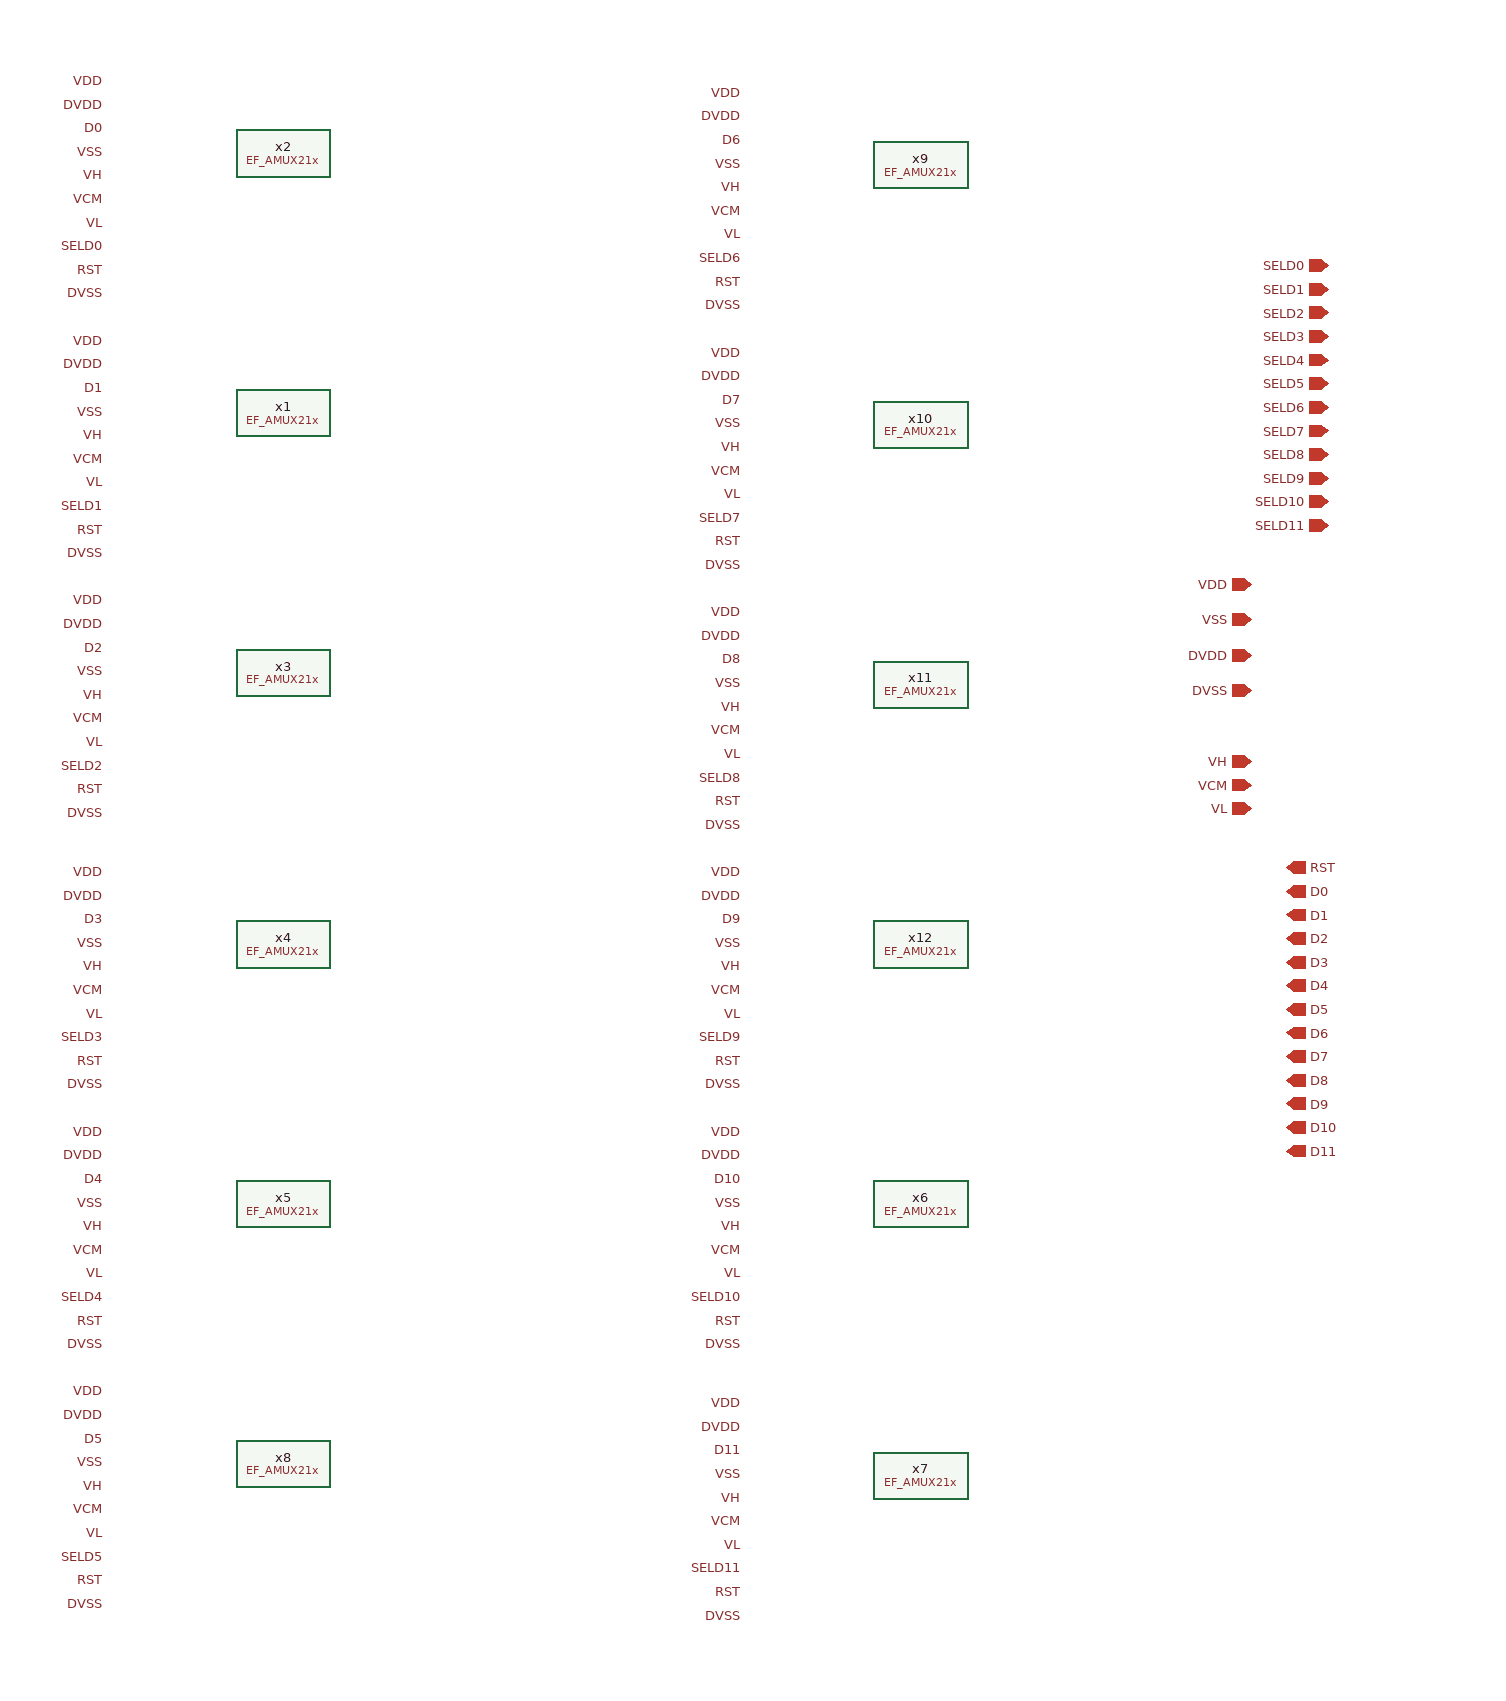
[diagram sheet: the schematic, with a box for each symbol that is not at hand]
v {xschem version=3.4.5 file_version=1.2
}
G {}
K {}
V {}
S {}
E {}
C {devices/lab_pin.sym} 1120 -1085 0 0 {name=p6 sig_type=std_logic lab=VDD}
C {devices/lab_pin.sym} 1120 -1065 0 0 {name=p8 sig_type=std_logic lab=DVDD}
C {EF_AMUX21x.sym} 1270 -1025 0 0 {name=x2}
C {devices/lab_pin.sym} 1120 -1045 0 0 {name=p17 sig_type=std_logic lab=D0}
C {devices/lab_pin.sym} 1120 -1005 0 0 {name=p23 sig_type=std_logic lab=VH}
C {devices/lab_pin.sym} 1120 -945 0 0 {name=p11 sig_type=std_logic lab=SELD0}
C {devices/lab_pin.sym} 1120 -905 0 0 {name=p19 sig_type=std_logic lab=DVSS}
C {devices/lab_pin.sym} 1120 -965 0 0 {name=p22 sig_type=std_logic lab=VL}
C {devices/iopin.sym} 2090 -660 0 0 {name=p32 lab=VDD}
C {devices/iopin.sym} 2090 -600 0 0 {name=p33 lab=DVDD}
C {devices/iopin.sym} 2090 -570 0 0 {name=p34 lab=DVSS}
C {devices/iopin.sym} 2090 -510 0 0 {name=p36 lab=VH}
C {devices/lab_pin.sym} 1120 -865 0 0 {name=p12 sig_type=std_logic lab=VDD}
C {devices/lab_pin.sym} 1120 -845 0 0 {name=p13 sig_type=std_logic lab=DVDD}
C {EF_AMUX21x.sym} 1270 -805 0 0 {name=x1}
C {devices/lab_pin.sym} 1120 -825 0 0 {name=p14 sig_type=std_logic lab=D1}
C {devices/lab_pin.sym} 1120 -725 0 0 {name=p18 sig_type=std_logic lab=SELD1}
C {devices/lab_pin.sym} 1120 -685 0 0 {name=p20 sig_type=std_logic lab=DVSS}
C {devices/iopin.sym} 2090 -470 0 0 {name=p4 lab=VL}
C {devices/lab_pin.sym} 1120 -645 0 0 {name=p21 sig_type=std_logic lab=VDD}
C {devices/lab_pin.sym} 1120 -625 0 0 {name=p24 sig_type=std_logic lab=DVDD}
C {EF_AMUX21x.sym} 1270 -585 0 0 {name=x3}
C {devices/lab_pin.sym} 1120 -605 0 0 {name=p25 sig_type=std_logic lab=D2}
C {devices/lab_pin.sym} 1120 -505 0 0 {name=p28 sig_type=std_logic lab=SELD2}
C {devices/lab_pin.sym} 1120 -465 0 0 {name=p29 sig_type=std_logic lab=DVSS}
C {devices/lab_pin.sym} 1120 -415 0 0 {name=p7 sig_type=std_logic lab=VDD}
C {devices/lab_pin.sym} 1120 -395 0 0 {name=p10 sig_type=std_logic lab=DVDD}
C {EF_AMUX21x.sym} 1270 -355 0 0 {name=x4}
C {devices/lab_pin.sym} 1120 -375 0 0 {name=p30 sig_type=std_logic lab=D3}
C {devices/lab_pin.sym} 1120 -275 0 0 {name=p31 sig_type=std_logic lab=SELD3}
C {devices/lab_pin.sym} 1120 -235 0 0 {name=p35 sig_type=std_logic lab=DVSS}
C {devices/lab_pin.sym} 1120 -195 0 0 {name=p44 sig_type=std_logic lab=VDD}
C {devices/lab_pin.sym} 1120 -175 0 0 {name=p45 sig_type=std_logic lab=DVDD}
C {EF_AMUX21x.sym} 1270 -135 0 0 {name=x5}
C {devices/lab_pin.sym} 1120 -155 0 0 {name=p46 sig_type=std_logic lab=D4}
C {devices/lab_pin.sym} 1120 -55 0 0 {name=p47 sig_type=std_logic lab=SELD4}
C {devices/lab_pin.sym} 1120 -15 0 0 {name=p48 sig_type=std_logic lab=DVSS}
C {devices/lab_pin.sym} 1120 25 0 0 {name=p74 sig_type=std_logic lab=VDD}
C {devices/lab_pin.sym} 1120 45 0 0 {name=p75 sig_type=std_logic lab=DVDD}
C {EF_AMUX21x.sym} 1270 85 0 0 {name=x8}
C {devices/lab_pin.sym} 1120 65 0 0 {name=p76 sig_type=std_logic lab=D5}
C {devices/lab_pin.sym} 1120 165 0 0 {name=p77 sig_type=std_logic lab=SELD5}
C {devices/lab_pin.sym} 1120 205 0 0 {name=p78 sig_type=std_logic lab=DVSS}
C {devices/lab_pin.sym} 1660 -1075 0 0 {name=p86 sig_type=std_logic lab=VDD}
C {devices/lab_pin.sym} 1660 -1055 0 0 {name=p87 sig_type=std_logic lab=DVDD}
C {EF_AMUX21x.sym} 1810 -1015 0 0 {name=x9}
C {devices/lab_pin.sym} 1660 -1035 0 0 {name=p88 sig_type=std_logic lab=D6}
C {devices/lab_pin.sym} 1660 -935 0 0 {name=p89 sig_type=std_logic lab=SELD6}
C {devices/lab_pin.sym} 1660 -895 0 0 {name=p90 sig_type=std_logic lab=DVSS}
C {devices/lab_pin.sym} 1660 -855 0 0 {name=p96 sig_type=std_logic lab=VDD}
C {devices/lab_pin.sym} 1660 -835 0 0 {name=p97 sig_type=std_logic lab=DVDD}
C {EF_AMUX21x.sym} 1810 -795 0 0 {name=x10}
C {devices/lab_pin.sym} 1660 -815 0 0 {name=p98 sig_type=std_logic lab=D7}
C {devices/lab_pin.sym} 1660 -715 0 0 {name=p99 sig_type=std_logic lab=SELD7}
C {devices/lab_pin.sym} 1660 -675 0 0 {name=p100 sig_type=std_logic lab=DVSS}
C {devices/lab_pin.sym} 1660 -635 0 0 {name=p106 sig_type=std_logic lab=VDD}
C {devices/lab_pin.sym} 1660 -615 0 0 {name=p107 sig_type=std_logic lab=DVDD}
C {EF_AMUX21x.sym} 1810 -575 0 0 {name=x11}
C {devices/lab_pin.sym} 1660 -595 0 0 {name=p108 sig_type=std_logic lab=D8}
C {devices/lab_pin.sym} 1660 -495 0 0 {name=p109 sig_type=std_logic lab=SELD8}
C {devices/lab_pin.sym} 1660 -455 0 0 {name=p110 sig_type=std_logic lab=DVSS}
C {devices/lab_pin.sym} 1660 -415 0 0 {name=p116 sig_type=std_logic lab=VDD}
C {devices/lab_pin.sym} 1660 -395 0 0 {name=p117 sig_type=std_logic lab=DVDD}
C {EF_AMUX21x.sym} 1810 -355 0 0 {name=x12}
C {devices/lab_pin.sym} 1660 -375 0 0 {name=p118 sig_type=std_logic lab=D9}
C {devices/lab_pin.sym} 1660 -275 0 0 {name=p119 sig_type=std_logic lab=SELD9}
C {devices/lab_pin.sym} 1660 -235 0 0 {name=p120 sig_type=std_logic lab=DVSS}
C {devices/ipin.sym} 2155 -930 0 0 {name=p61 lab=SELD0}
C {devices/ipin.sym} 2155 -910 0 0 {name=p62 lab=SELD1}
C {devices/ipin.sym} 2155 -890 0 0 {name=p63 lab=SELD2}
C {devices/ipin.sym} 2155 -870 0 0 {name=p64 lab=SELD3}
C {devices/ipin.sym} 2155 -850 0 0 {name=p65 lab=SELD4}
C {devices/ipin.sym} 2155 -830 0 0 {name=p66 lab=SELD5}
C {devices/ipin.sym} 2155 -810 0 0 {name=p67 lab=SELD6}
C {devices/ipin.sym} 2155 -790 0 0 {name=p68 lab=SELD7}
C {devices/ipin.sym} 2155 -770 0 0 {name=p69 lab=SELD8}
C {devices/ipin.sym} 2155 -750 0 0 {name=p70 lab=SELD9}
C {devices/iopin.sym} 2090 -630 0 0 {name=p71 lab=VSS}
C {devices/lab_pin.sym} 1120 -1025 0 0 {name=p72 sig_type=std_logic lab=VSS}
C {devices/lab_pin.sym} 1120 -805 0 0 {name=p73 sig_type=std_logic lab=VSS}
C {devices/lab_pin.sym} 1120 -355 0 0 {name=p80 sig_type=std_logic lab=VSS}
C {devices/lab_pin.sym} 1120 -135 0 0 {name=p81 sig_type=std_logic lab=VSS}
C {devices/lab_pin.sym} 1120 85 0 0 {name=p82 sig_type=std_logic lab=VSS}
C {devices/lab_pin.sym} 1660 -1015 0 0 {name=p83 sig_type=std_logic lab=VSS}
C {devices/lab_pin.sym} 1660 -795 0 0 {name=p84 sig_type=std_logic lab=VSS}
C {devices/lab_pin.sym} 1660 -575 0 0 {name=p85 sig_type=std_logic lab=VSS}
C {devices/lab_pin.sym} 1660 -355 0 0 {name=p91 sig_type=std_logic lab=VSS}
C {devices/iopin.sym} 2120 -400 0 1 {name=p92 lab=D0}
C {devices/iopin.sym} 2120 -380 0 1 {name=p93 lab=D1}
C {devices/iopin.sym} 2120 -360 0 1 {name=p94 lab=D2}
C {devices/iopin.sym} 2120 -340 0 1 {name=p95 lab=D3}
C {devices/iopin.sym} 2120 -320 0 1 {name=p101 lab=D4}
C {devices/iopin.sym} 2120 -300 0 1 {name=p102 lab=D5}
C {devices/iopin.sym} 2120 -280 0 1 {name=p103 lab=D6}
C {devices/iopin.sym} 2120 -260 0 1 {name=p104 lab=D7}
C {devices/iopin.sym} 2120 -240 0 1 {name=p105 lab=D8}
C {devices/iopin.sym} 2120 -220 0 1 {name=p111 lab=D9}
C {devices/ipin.sym} 2155 -730 0 0 {name=p1 lab=SELD10}
C {devices/ipin.sym} 2155 -710 0 0 {name=p2 lab=SELD11}
C {devices/iopin.sym} 2120 -200 0 1 {name=p3 lab=D10}
C {devices/iopin.sym} 2120 -180 0 1 {name=p16 lab=D11}
C {devices/lab_pin.sym} 1660 -195 0 0 {name=p27 sig_type=std_logic lab=VDD}
C {devices/lab_pin.sym} 1660 -175 0 0 {name=p37 sig_type=std_logic lab=DVDD}
C {EF_AMUX21x.sym} 1810 -135 0 0 {name=x6}
C {devices/lab_pin.sym} 1660 -155 0 0 {name=p40 sig_type=std_logic lab=D10}
C {devices/lab_pin.sym} 1660 -55 0 0 {name=p41 sig_type=std_logic lab=SELD10}
C {devices/lab_pin.sym} 1660 -15 0 0 {name=p42 sig_type=std_logic lab=DVSS}
C {devices/lab_pin.sym} 1660 -135 0 0 {name=p113 sig_type=std_logic lab=VSS}
C {devices/lab_pin.sym} 1660 35 0 0 {name=p114 sig_type=std_logic lab=VDD}
C {devices/lab_pin.sym} 1660 55 0 0 {name=p115 sig_type=std_logic lab=DVDD}
C {EF_AMUX21x.sym} 1810 95 0 0 {name=x7}
C {devices/lab_pin.sym} 1660 75 0 0 {name=p121 sig_type=std_logic lab=D11}
C {devices/lab_pin.sym} 1660 175 0 0 {name=p122 sig_type=std_logic lab=SELD11}
C {devices/lab_pin.sym} 1660 215 0 0 {name=p123 sig_type=std_logic lab=DVSS}
C {devices/lab_pin.sym} 1660 95 0 0 {name=p126 sig_type=std_logic lab=VSS}
C {devices/iopin.sym} 2090 -490 0 0 {name=p127 lab=VCM}
C {devices/iopin.sym} 2120 -420 0 1 {name=p128 lab=RST}
C {devices/lab_pin.sym} 1120 -985 0 0 {name=p129 sig_type=std_logic lab=VCM}
C {devices/lab_pin.sym} 1120 -765 0 0 {name=p130 sig_type=std_logic lab=VCM}
C {devices/lab_pin.sym} 1120 -545 0 0 {name=p131 sig_type=std_logic lab=VCM}
C {devices/lab_pin.sym} 1120 -315 0 0 {name=p132 sig_type=std_logic lab=VCM}
C {devices/lab_pin.sym} 1120 -95 0 0 {name=p133 sig_type=std_logic lab=VCM}
C {devices/lab_pin.sym} 1120 125 0 0 {name=p134 sig_type=std_logic lab=VCM}
C {devices/lab_pin.sym} 1660 135 0 0 {name=p135 sig_type=std_logic lab=VCM}
C {devices/lab_pin.sym} 1660 -95 0 0 {name=p136 sig_type=std_logic lab=VCM}
C {devices/lab_pin.sym} 1660 -315 0 0 {name=p137 sig_type=std_logic lab=VCM}
C {devices/lab_pin.sym} 1660 -535 0 0 {name=p138 sig_type=std_logic lab=VCM}
C {devices/lab_pin.sym} 1660 -755 0 0 {name=p139 sig_type=std_logic lab=VCM}
C {devices/lab_pin.sym} 1660 -975 0 0 {name=p140 sig_type=std_logic lab=VCM}
C {devices/lab_pin.sym} 1120 -925 0 0 {name=p141 sig_type=std_logic lab=RST}
C {devices/lab_pin.sym} 1120 -705 0 0 {name=p142 sig_type=std_logic lab=RST}
C {devices/lab_pin.sym} 1120 -485 0 0 {name=p143 sig_type=std_logic lab=RST}
C {devices/lab_pin.sym} 1120 -255 0 0 {name=p144 sig_type=std_logic lab=RST}
C {devices/lab_pin.sym} 1120 -35 0 0 {name=p145 sig_type=std_logic lab=RST}
C {devices/lab_pin.sym} 1120 185 0 0 {name=p146 sig_type=std_logic lab=RST}
C {devices/lab_pin.sym} 1660 195 0 0 {name=p147 sig_type=std_logic lab=RST}
C {devices/lab_pin.sym} 1660 -35 0 0 {name=p148 sig_type=std_logic lab=RST}
C {devices/lab_pin.sym} 1660 -255 0 0 {name=p149 sig_type=std_logic lab=RST}
C {devices/lab_pin.sym} 1660 -475 0 0 {name=p150 sig_type=std_logic lab=RST}
C {devices/lab_pin.sym} 1660 -695 0 0 {name=p151 sig_type=std_logic lab=RST}
C {devices/lab_pin.sym} 1660 -915 0 0 {name=p152 sig_type=std_logic lab=RST}
C {devices/lab_pin.sym} 1120 -745 0 0 {name=p15 sig_type=std_logic lab=VL}
C {devices/lab_pin.sym} 1120 -525 0 0 {name=p43 sig_type=std_logic lab=VL}
C {devices/lab_pin.sym} 1120 -585 0 0 {name=p5 sig_type=std_logic lab=VSS}
C {devices/lab_pin.sym} 1120 -295 0 0 {name=p38 sig_type=std_logic lab=VL}
C {devices/lab_pin.sym} 1120 -75 0 0 {name=p50 sig_type=std_logic lab=VL}
C {devices/lab_pin.sym} 1120 145 0 0 {name=p52 sig_type=std_logic lab=VL}
C {devices/lab_pin.sym} 1660 155 0 0 {name=p54 sig_type=std_logic lab=VL}
C {devices/lab_pin.sym} 1660 -75 0 0 {name=p56 sig_type=std_logic lab=VL}
C {devices/lab_pin.sym} 1660 -295 0 0 {name=p58 sig_type=std_logic lab=VL}
C {devices/lab_pin.sym} 1660 -515 0 0 {name=p60 sig_type=std_logic lab=VL}
C {devices/lab_pin.sym} 1660 -735 0 0 {name=p112 sig_type=std_logic lab=VL}
C {devices/lab_pin.sym} 1660 -955 0 0 {name=p125 sig_type=std_logic lab=VL}
C {devices/lab_pin.sym} 1120 -785 0 0 {name=p9 sig_type=std_logic lab=VH}
C {devices/lab_pin.sym} 1120 -335 0 0 {name=p26 sig_type=std_logic lab=VH}
C {devices/lab_pin.sym} 1120 -565 0 0 {name=p39 sig_type=std_logic lab=VH}
C {devices/lab_pin.sym} 1120 -115 0 0 {name=p49 sig_type=std_logic lab=VH}
C {devices/lab_pin.sym} 1120 105 0 0 {name=p51 sig_type=std_logic lab=VH}
C {devices/lab_pin.sym} 1660 -995 0 0 {name=p53 sig_type=std_logic lab=VH}
C {devices/lab_pin.sym} 1660 -775 0 0 {name=p55 sig_type=std_logic lab=VH}
C {devices/lab_pin.sym} 1660 -555 0 0 {name=p57 sig_type=std_logic lab=VH}
C {devices/lab_pin.sym} 1660 -335 0 0 {name=p59 sig_type=std_logic lab=VH}
C {devices/lab_pin.sym} 1660 -115 0 0 {name=p79 sig_type=std_logic lab=VH}
C {devices/lab_pin.sym} 1660 115 0 0 {name=p124 sig_type=std_logic lab=VH}
